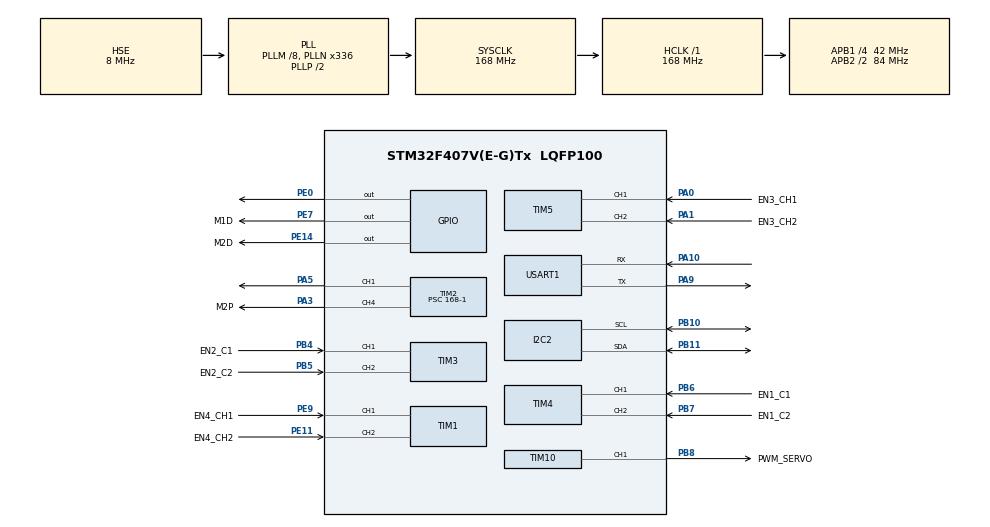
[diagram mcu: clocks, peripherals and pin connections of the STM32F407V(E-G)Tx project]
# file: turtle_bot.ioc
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Mcu.Family=STM32F4
Mcu.Name=STM32F407V(E-G)Tx
Mcu.Package=LQFP100
NVIC.PriorityGroup=NVIC_PRIORITYGROUP_0
PA0-WKUP.GPIO_Label=EN3_CH1
PA0-WKUP.Signal=S_TIM5_CH1
PA1.GPIO_Label=EN3_CH2
PA1.Signal=S_TIM5_CH2
PA10.Mode=Asynchronous
PA10.Signal=USART1_RX
PA3.GPIO_Label=M2P
PA3.Signal=S_TIM2_CH4
PA5.Signal=S_TIM2_CH1_ETR
PA9.Mode=Asynchronous
PA9.Signal=USART1_TX
PB10.Mode=I2C
PB10.Signal=I2C2_SCL
PB11.Mode=I2C
PB11.Signal=I2C2_SDA
PB4.GPIO_Label=EN2_C1
PB4.Signal=S_TIM3_CH1
PB5.GPIO_Label=EN2_C2
PB5.Signal=S_TIM3_CH2
PB6.GPIO_Label=EN1_C1
PB6.Signal=S_TIM4_CH1
PB7.GPIO_Label=EN1_C2
PB7.Signal=S_TIM4_CH2
PB8.GPIO_Label=PWM_SERVO
PB8.Signal=S_TIM10_CH1
PE0.Signal=GPIO_Output
PE11.GPIO_Label=EN4_CH2
PE11.Signal=S_TIM1_CH2
PE14.GPIO_Label=M2D
PE14.Signal=GPIO_Output
PE7.GPIO_Label=M1D
PE7.Signal=GPIO_Output
PE9.GPIO_Label=EN4_CH1
PE9.Signal=S_TIM1_CH1
PH0-OSC_IN.Mode=HSE-External-Oscillator
PH0-OSC_IN.Signal=RCC_OSC_IN
PH1-OSC_OUT.Mode=HSE-External-Oscillator
PH1-OSC_OUT.Signal=RCC_OSC_OUT
ProjectManager.HeapSize=0x200
ProjectManager.StackSize=0x400
ProjectManager.TargetToolchain=Makefile
RCC.48MHZClocksFreq_Value=48000000
RCC.AHBFreq_Value=168000000
RCC.APB1CLKDivider=RCC_HCLK_DIV4
RCC.APB1Freq_Value=42000000
RCC.APB1TimFreq_Value=84000000
RCC.APB2CLKDivider=RCC_HCLK_DIV2
RCC.APB2Freq_Value=84000000
RCC.APB2TimFreq_Value=168000000
RCC.CortexFreq_Value=168000000
RCC.HCLKFreq_Value=168000000
RCC.HSE_VALUE=8000000
RCC.HSI_VALUE=16000000
RCC.LSE_VALUE=32768
RCC.PLLM=8
RCC.PLLN=336
RCC.PLLQ=7
RCC.PLLSourceVirtual=RCC_PLLSOURCE_HSE
RCC.SYSCLKFreq_VALUE=168000000
RCC.SYSCLKSource=RCC_SYSCLKSOURCE_PLLCLK
RCC.VCOOutputFreq_Value=336000000
SH.S_TIM10_CH1.0=TIM10_CH1,PWM Generation1 CH1
SH.S_TIM1_CH1.0=TIM1_CH1,Encoder_Interface
SH.S_TIM1_CH2.0=TIM1_CH2,Encoder_Interface
SH.S_TIM2_CH1_ETR.0=TIM2_CH1,PWM Generation1 CH1
SH.S_TIM2_CH4.0=TIM2_CH4,PWM Generation4 CH4
SH.S_TIM3_CH1.0=TIM3_CH1,Encoder_Interface
SH.S_TIM3_CH2.0=TIM3_CH2,Encoder_Interface
SH.S_TIM4_CH1.0=TIM4_CH1,Encoder_Interface
SH.S_TIM4_CH2.0=TIM4_CH2,Encoder_Interface
SH.S_TIM5_CH1.0=TIM5_CH1,Encoder_Interface
SH.S_TIM5_CH2.0=TIM5_CH2,Encoder_Interface
TIM1.EncoderMode=TIM_ENCODERMODE_TI12
TIM10.AutoReloadPreload=TIM_AUTORELOAD_PRELOAD_ENABLE
TIM10.Channel=TIM_CHANNEL_1
TIM14.AutoReloadPreload=TIM_AUTORELOAD_PRELOAD_ENABLE
TIM14.Period=500-1
TIM14.Prescaler=168-1
TIM2.AutoReloadPreload=TIM_AUTORELOAD_PRELOAD_ENABLE
TIM2.Channel-PWM\ Generation1\ CH1=TIM_CHANNEL_1
TIM2.Channel-PWM\ Generation4\ CH4=TIM_CHANNEL_4
TIM2.Period=500-1
TIM2.Prescaler=168-1
TIM3.EncoderMode=TIM_ENCODERMODE_TI12
TIM4.EncoderMode=TIM_ENCODERMODE_TI12
USART1.VirtualMode=VM_ASYNC
VP_TIM10_VS_ClockSourceINT.Mode=Enable_Timer
VP_TIM14_VS_ClockSourceINT.Mode=Enable_Timer
VP_TIM2_VS_ClockSourceINT.Mode=Internal
board=STM32F407G-DISC1

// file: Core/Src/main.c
/* USER CODE BEGIN Header */
/**
  ******************************************************************************
  * @file           : main.c
  * @brief          : Main program body
  ******************************************************************************
  * @attention
  *
  * Copyright (c) 2024 STMicroelectronics.
  * All rights reserved.
  *
  * This software is licensed under terms that can be found in the LICENSE file
  * in the root directory of this software component.
  * If no LICENSE file comes with this software, it is provided AS-IS.
  *
  ******************************************************************************
  */
/* USER CODE END Header */
#include "main.h"

/* USER CODE BEGIN Includes */

#include "stdint.h"

/* USER CODE END Includes */

I2C_HandleTypeDef hi2c2;

TIM_HandleTypeDef htim1;
TIM_HandleTypeDef htim2;
TIM_HandleTypeDef htim3;
TIM_HandleTypeDef htim4;
TIM_HandleTypeDef htim5;
TIM_HandleTypeDef htim10;
TIM_HandleTypeDef htim14;

UART_HandleTypeDef huart1;

void SystemClock_Config(void);
static void MX_GPIO_Init(void);
static void MX_TIM3_Init(void);
static void MX_TIM4_Init(void);
static void MX_USART1_UART_Init(void);
static void MX_I2C2_Init(void);
static void MX_TIM2_Init(void);
static void MX_TIM14_Init(void);
static void MX_TIM10_Init(void);
static void MX_TIM1_Init(void);
static void MX_TIM5_Init(void);

int main(void)
{

  /* MCU Configuration--------------------------------------------------------*/

  /* Reset of all peripherals, Initializes the Flash interface and the Systick. */
  HAL_Init();

  /* Configure the system clock */
  SystemClock_Config();

  /* Initialize all configured peripherals */
  MX_GPIO_Init();
  MX_TIM3_Init();
  MX_TIM4_Init();
  MX_USART1_UART_Init();
  MX_I2C2_Init();
  MX_TIM2_Init();
  MX_TIM14_Init();
  MX_TIM10_Init();
  MX_TIM1_Init();
  MX_TIM5_Init();
  /* USER CODE BEGIN 2 */

  HAL_TIM_PWM_Start(&htim2, TIM_CHANNEL_1);
  HAL_TIM_PWM_Start(&htim2, TIM_CHANNEL_4);

  /* USER CODE END 2 */

  /* Infinite loop */
  /* USER CODE BEGIN WHILE */

  while (1)
  {

    __HAL_TIM_SET_COMPARE(&htim2, TIM_CHANNEL_4, 250);
    TIM2->CCR1 = 250;
    TIM2->CCR4 = 250;

    HAL_Delay(1000);

    for (int i = 0; i < 500; i++) {
      TIM2->CCR1 = i;
      TIM2->CCR4 = i;

      HAL_Delay(5);
    }

    /* USER CODE END WHILE */

  }
}

void SystemClock_Config(void)
{
  RCC_OscInitTypeDef RCC_OscInitStruct = {0};
  RCC_ClkInitTypeDef RCC_ClkInitStruct = {0};

  /** Configure the main internal regulator output voltage
  */
  __HAL_RCC_PWR_CLK_ENABLE();
  __HAL_PWR_VOLTAGESCALING_CONFIG(PWR_REGULATOR_VOLTAGE_SCALE1);

  /** Initializes the RCC Oscillators according to the specified parameters
  * in the RCC_OscInitTypeDef structure.
  */
  RCC_OscInitStruct.OscillatorType = RCC_OSCILLATORTYPE_HSE;
  RCC_OscInitStruct.HSEState = RCC_HSE_ON;
  RCC_OscInitStruct.PLL.PLLState = RCC_PLL_ON;
  RCC_OscInitStruct.PLL.PLLSource = RCC_PLLSOURCE_HSE;
  RCC_OscInitStruct.PLL.PLLM = 8;
  RCC_OscInitStruct.PLL.PLLN = 336;
  RCC_OscInitStruct.PLL.PLLP = RCC_PLLP_DIV2;
  RCC_OscInitStruct.PLL.PLLQ = 7;
  if (HAL_RCC_OscConfig(&RCC_OscInitStruct) != HAL_OK)
  {
    Error_Handler();
  }

  /** Initializes the CPU, AHB and APB buses clocks
  */
  RCC_ClkInitStruct.ClockType = RCC_CLOCKTYPE_HCLK|RCC_CLOCKTYPE_SYSCLK
                              |RCC_CLOCKTYPE_PCLK1|RCC_CLOCKTYPE_PCLK2;
  RCC_ClkInitStruct.SYSCLKSource = RCC_SYSCLKSOURCE_PLLCLK;
  RCC_ClkInitStruct.AHBCLKDivider = RCC_SYSCLK_DIV1;
  RCC_ClkInitStruct.APB1CLKDivider = RCC_HCLK_DIV4;
  RCC_ClkInitStruct.APB2CLKDivider = RCC_HCLK_DIV2;

  if (HAL_RCC_ClockConfig(&RCC_ClkInitStruct, FLASH_LATENCY_5) != HAL_OK)
  {
    Error_Handler();
  }
}

static void MX_I2C2_Init(void)
{

  hi2c2.Instance = I2C2;
  hi2c2.Init.ClockSpeed = 100000;
  hi2c2.Init.DutyCycle = I2C_DUTYCYCLE_2;
  hi2c2.Init.OwnAddress1 = 0;
  hi2c2.Init.AddressingMode = I2C_ADDRESSINGMODE_7BIT;
  hi2c2.Init.DualAddressMode = I2C_DUALADDRESS_DISABLE;
  hi2c2.Init.OwnAddress2 = 0;
  hi2c2.Init.GeneralCallMode = I2C_GENERALCALL_DISABLE;
  hi2c2.Init.NoStretchMode = I2C_NOSTRETCH_DISABLE;
  if (HAL_I2C_Init(&hi2c2) != HAL_OK)
  {
    Error_Handler();
  }

}

static void MX_TIM1_Init(void)
{

  TIM_Encoder_InitTypeDef sConfig = {0};
  TIM_MasterConfigTypeDef sMasterConfig = {0};

  htim1.Instance = TIM1;
  htim1.Init.Prescaler = 0;
  htim1.Init.CounterMode = TIM_COUNTERMODE_UP;
  htim1.Init.Period = 65535;
  htim1.Init.ClockDivision = TIM_CLOCKDIVISION_DIV1;
  htim1.Init.RepetitionCounter = 0;
  htim1.Init.AutoReloadPreload = TIM_AUTORELOAD_PRELOAD_DISABLE;
  sConfig.EncoderMode = TIM_ENCODERMODE_TI12;
  sConfig.IC1Polarity = TIM_ICPOLARITY_RISING;
  sConfig.IC1Selection = TIM_ICSELECTION_DIRECTTI;
  sConfig.IC1Prescaler = TIM_ICPSC_DIV1;
  sConfig.IC1Filter = 0;
  sConfig.IC2Polarity = TIM_ICPOLARITY_RISING;
  sConfig.IC2Selection = TIM_ICSELECTION_DIRECTTI;
  sConfig.IC2Prescaler = TIM_ICPSC_DIV1;
  sConfig.IC2Filter = 0;
  if (HAL_TIM_Encoder_Init(&htim1, &sConfig) != HAL_OK)
  {
    Error_Handler();
  }
  sMasterConfig.MasterOutputTrigger = TIM_TRGO_RESET;
  sMasterConfig.MasterSlaveMode = TIM_MASTERSLAVEMODE_DISABLE;
  if (HAL_TIMEx_MasterConfigSynchronization(&htim1, &sMasterConfig) != HAL_OK)
  {
    Error_Handler();
  }

}

static void MX_TIM2_Init(void)
{

  TIM_ClockConfigTypeDef sClockSourceConfig = {0};
  TIM_MasterConfigTypeDef sMasterConfig = {0};
  TIM_OC_InitTypeDef sConfigOC = {0};

  htim2.Instance = TIM2;
  htim2.Init.Prescaler = 168-1;
  htim2.Init.CounterMode = TIM_COUNTERMODE_UP;
  htim2.Init.Period = 500-1;
  htim2.Init.ClockDivision = TIM_CLOCKDIVISION_DIV1;
  htim2.Init.AutoReloadPreload = TIM_AUTORELOAD_PRELOAD_ENABLE;
  if (HAL_TIM_Base_Init(&htim2) != HAL_OK)
  {
    Error_Handler();
  }
  sClockSourceConfig.ClockSource = TIM_CLOCKSOURCE_INTERNAL;
  if (HAL_TIM_ConfigClockSource(&htim2, &sClockSourceConfig) != HAL_OK)
  {
    Error_Handler();
  }
  if (HAL_TIM_PWM_Init(&htim2) != HAL_OK)
  {
    Error_Handler();
  }
  sMasterConfig.MasterOutputTrigger = TIM_TRGO_RESET;
  sMasterConfig.MasterSlaveMode = TIM_MASTERSLAVEMODE_DISABLE;
  if (HAL_TIMEx_MasterConfigSynchronization(&htim2, &sMasterConfig) != HAL_OK)
  {
    Error_Handler();
  }
  sConfigOC.OCMode = TIM_OCMODE_PWM1;
  sConfigOC.Pulse = 0;
  sConfigOC.OCPolarity = TIM_OCPOLARITY_HIGH;
  sConfigOC.OCFastMode = TIM_OCFAST_DISABLE;
  if (HAL_TIM_PWM_ConfigChannel(&htim2, &sConfigOC, TIM_CHANNEL_1) != HAL_OK)
  {
    Error_Handler();
  }
  if (HAL_TIM_PWM_ConfigChannel(&htim2, &sConfigOC, TIM_CHANNEL_4) != HAL_OK)
  {
    Error_Handler();
  }
  HAL_TIM_MspPostInit(&htim2);

}

static void MX_TIM3_Init(void)
{

  TIM_Encoder_InitTypeDef sConfig = {0};
  TIM_MasterConfigTypeDef sMasterConfig = {0};

  htim3.Instance = TIM3;
  htim3.Init.Prescaler = 0;
  htim3.Init.CounterMode = TIM_COUNTERMODE_UP;
  htim3.Init.Period = 65535;
  htim3.Init.ClockDivision = TIM_CLOCKDIVISION_DIV1;
  htim3.Init.AutoReloadPreload = TIM_AUTORELOAD_PRELOAD_DISABLE;
  sConfig.EncoderMode = TIM_ENCODERMODE_TI12;
  sConfig.IC1Polarity = TIM_ICPOLARITY_RISING;
  sConfig.IC1Selection = TIM_ICSELECTION_DIRECTTI;
  sConfig.IC1Prescaler = TIM_ICPSC_DIV1;
  sConfig.IC1Filter = 0;
  sConfig.IC2Polarity = TIM_ICPOLARITY_RISING;
  sConfig.IC2Selection = TIM_ICSELECTION_DIRECTTI;
  sConfig.IC2Prescaler = TIM_ICPSC_DIV1;
  sConfig.IC2Filter = 0;
  if (HAL_TIM_Encoder_Init(&htim3, &sConfig) != HAL_OK)
  {
    Error_Handler();
  }
  sMasterConfig.MasterOutputTrigger = TIM_TRGO_RESET;
  sMasterConfig.MasterSlaveMode = TIM_MASTERSLAVEMODE_DISABLE;
  if (HAL_TIMEx_MasterConfigSynchronization(&htim3, &sMasterConfig) != HAL_OK)
  {
    Error_Handler();
  }

}

static void MX_TIM4_Init(void)
{

  TIM_Encoder_InitTypeDef sConfig = {0};
  TIM_MasterConfigTypeDef sMasterConfig = {0};

  htim4.Instance = TIM4;
  htim4.Init.Prescaler = 0;
  htim4.Init.CounterMode = TIM_COUNTERMODE_UP;
  htim4.Init.Period = 65535;
  htim4.Init.ClockDivision = TIM_CLOCKDIVISION_DIV1;
  htim4.Init.AutoReloadPreload = TIM_AUTORELOAD_PRELOAD_DISABLE;
  sConfig.EncoderMode = TIM_ENCODERMODE_TI12;
  sConfig.IC1Polarity = TIM_ICPOLARITY_RISING;
  sConfig.IC1Selection = TIM_ICSELECTION_DIRECTTI;
  sConfig.IC1Prescaler = TIM_ICPSC_DIV1;
  sConfig.IC1Filter = 0;
  sConfig.IC2Polarity = TIM_ICPOLARITY_RISING;
  sConfig.IC2Selection = TIM_ICSELECTION_DIRECTTI;
  sConfig.IC2Prescaler = TIM_ICPSC_DIV1;
  sConfig.IC2Filter = 0;
  if (HAL_TIM_Encoder_Init(&htim4, &sConfig) != HAL_OK)
  {
    Error_Handler();
  }
  sMasterConfig.MasterOutputTrigger = TIM_TRGO_RESET;
  sMasterConfig.MasterSlaveMode = TIM_MASTERSLAVEMODE_DISABLE;
  if (HAL_TIMEx_MasterConfigSynchronization(&htim4, &sMasterConfig) != HAL_OK)
  {
    Error_Handler();
  }

}

static void MX_TIM5_Init(void)
{

  TIM_Encoder_InitTypeDef sConfig = {0};
  TIM_MasterConfigTypeDef sMasterConfig = {0};

  htim5.Instance = TIM5;
  htim5.Init.Prescaler = 0;
  htim5.Init.CounterMode = TIM_COUNTERMODE_UP;
  htim5.Init.Period = 4294967295;
  htim5.Init.ClockDivision = TIM_CLOCKDIVISION_DIV1;
  htim5.Init.AutoReloadPreload = TIM_AUTORELOAD_PRELOAD_DISABLE;
  sConfig.EncoderMode = TIM_ENCODERMODE_TI1;
  sConfig.IC1Polarity = TIM_ICPOLARITY_RISING;
  sConfig.IC1Selection = TIM_ICSELECTION_DIRECTTI;
  sConfig.IC1Prescaler = TIM_ICPSC_DIV1;
  sConfig.IC1Filter = 0;
  sConfig.IC2Polarity = TIM_ICPOLARITY_RISING;
  sConfig.IC2Selection = TIM_ICSELECTION_DIRECTTI;
  sConfig.IC2Prescaler = TIM_ICPSC_DIV1;
  sConfig.IC2Filter = 0;
  if (HAL_TIM_Encoder_Init(&htim5, &sConfig) != HAL_OK)
  {
    Error_Handler();
  }
  sMasterConfig.MasterOutputTrigger = TIM_TRGO_RESET;
  sMasterConfig.MasterSlaveMode = TIM_MASTERSLAVEMODE_DISABLE;
  if (HAL_TIMEx_MasterConfigSynchronization(&htim5, &sMasterConfig) != HAL_OK)
  {
    Error_Handler();
  }

}

static void MX_TIM10_Init(void)
{

  TIM_OC_InitTypeDef sConfigOC = {0};

  htim10.Instance = TIM10;
  htim10.Init.Prescaler = 0;
  htim10.Init.CounterMode = TIM_COUNTERMODE_UP;
  htim10.Init.Period = 65535;
  htim10.Init.ClockDivision = TIM_CLOCKDIVISION_DIV1;
  htim10.Init.AutoReloadPreload = TIM_AUTORELOAD_PRELOAD_ENABLE;
  if (HAL_TIM_Base_Init(&htim10) != HAL_OK)
  {
    Error_Handler();
  }
  if (HAL_TIM_PWM_Init(&htim10) != HAL_OK)
  {
    Error_Handler();
  }
  sConfigOC.OCMode = TIM_OCMODE_PWM1;
  sConfigOC.Pulse = 0;
  sConfigOC.OCPolarity = TIM_OCPOLARITY_HIGH;
  sConfigOC.OCFastMode = TIM_OCFAST_DISABLE;
  if (HAL_TIM_PWM_ConfigChannel(&htim10, &sConfigOC, TIM_CHANNEL_1) != HAL_OK)
  {
    Error_Handler();
  }
  HAL_TIM_MspPostInit(&htim10);

}

static void MX_TIM14_Init(void)
{

  htim14.Instance = TIM14;
  htim14.Init.Prescaler = 168-1;
  htim14.Init.CounterMode = TIM_COUNTERMODE_UP;
  htim14.Init.Period = 500-1;
  htim14.Init.ClockDivision = TIM_CLOCKDIVISION_DIV1;
  htim14.Init.AutoReloadPreload = TIM_AUTORELOAD_PRELOAD_ENABLE;
  if (HAL_TIM_Base_Init(&htim14) != HAL_OK)
  {
    Error_Handler();
  }

}

static void MX_USART1_UART_Init(void)
{

  huart1.Instance = USART1;
  huart1.Init.BaudRate = 115200;
  huart1.Init.WordLength = UART_WORDLENGTH_8B;
  huart1.Init.StopBits = UART_STOPBITS_1;
  huart1.Init.Parity = UART_PARITY_NONE;
  huart1.Init.Mode = UART_MODE_TX_RX;
  huart1.Init.HwFlowCtl = UART_HWCONTROL_NONE;
  huart1.Init.OverSampling = UART_OVERSAMPLING_16;
  if (HAL_UART_Init(&huart1) != HAL_OK)
  {
    Error_Handler();
  }

}

static void MX_GPIO_Init(void)
{
  GPIO_InitTypeDef GPIO_InitStruct = {0};

  /* GPIO Ports Clock Enable */
  __HAL_RCC_GPIOE_CLK_ENABLE();
  __HAL_RCC_GPIOC_CLK_ENABLE();
  __HAL_RCC_GPIOH_CLK_ENABLE();
  __HAL_RCC_GPIOA_CLK_ENABLE();
  __HAL_RCC_GPIOB_CLK_ENABLE();

  /*Configure GPIO pin Output Level */
  HAL_GPIO_WritePin(GPIOE, M3D_Pin|M1D_Pin|M2D_Pin|GPIO_PIN_0, GPIO_PIN_RESET);

  /*Configure GPIO pin Output Level */
  HAL_GPIO_WritePin(M4D_GPIO_Port, M4D_Pin, GPIO_PIN_RESET);

  /*Configure GPIO pins : M3D_Pin M1D_Pin M2D_Pin PE0 */
  GPIO_InitStruct.Pin = M3D_Pin|M1D_Pin|M2D_Pin|GPIO_PIN_0;
  GPIO_InitStruct.Mode = GPIO_MODE_OUTPUT_PP;
  GPIO_InitStruct.Pull = GPIO_NOPULL;
  GPIO_InitStruct.Speed = GPIO_SPEED_FREQ_LOW;
  HAL_GPIO_Init(GPIOE, &GPIO_InitStruct);

  /*Configure GPIO pins : M3P_Pin M4P_Pin */
  GPIO_InitStruct.Pin = M3P_Pin|M4P_Pin;
  GPIO_InitStruct.Mode = GPIO_MODE_AF_PP;
  GPIO_InitStruct.Pull = GPIO_NOPULL;
  GPIO_InitStruct.Speed = GPIO_SPEED_FREQ_LOW;
  GPIO_InitStruct.Alternate = GPIO_AF3_TIM9;
  HAL_GPIO_Init(GPIOE, &GPIO_InitStruct);

  /*Configure GPIO pin : M4D_Pin */
  GPIO_InitStruct.Pin = M4D_Pin;
  GPIO_InitStruct.Mode = GPIO_MODE_OUTPUT_PP;
  GPIO_InitStruct.Pull = GPIO_NOPULL;
  GPIO_InitStruct.Speed = GPIO_SPEED_FREQ_LOW;
  HAL_GPIO_Init(M4D_GPIO_Port, &GPIO_InitStruct);

}

void Error_Handler(void)
{
  __disable_irq();
  while (1)
  {
  }
}
